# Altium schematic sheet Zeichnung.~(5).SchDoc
size A4

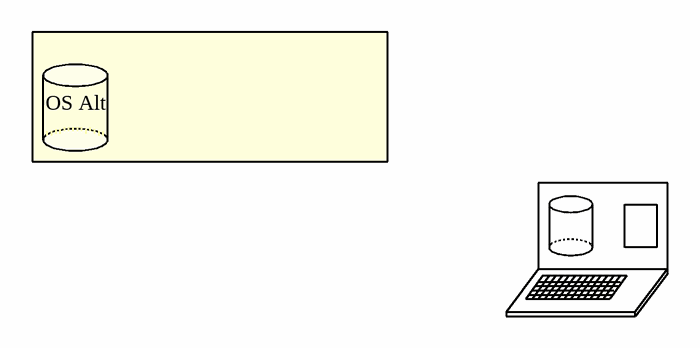
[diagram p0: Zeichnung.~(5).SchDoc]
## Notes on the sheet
- OS Alt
